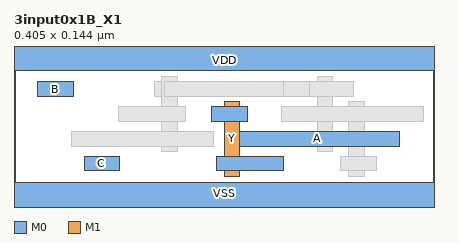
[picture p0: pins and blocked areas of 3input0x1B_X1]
MACRO 3input0x1B_X1
  CLASS CORE ;
  ORIGIN 0 0 ;
  FOREIGN 3input0x1B_X1 0 0 ;
  SIZE 0.4050 BY 0.1440 ;
  SYMMETRY X Y ;
  SITE coresite ;
  PIN A
    DIRECTION INPUT ;
    USE SIGNAL ;
    PORT
      LAYER M0 ;
        RECT 0.2130 0.0530 0.3720 0.0670 ;
    END
  END A
  PIN B
    DIRECTION INPUT ;
    USE SIGNAL ;
    PORT
      LAYER M0 ;
        RECT 0.0225 0.1010 0.0570 0.1150 ;
    END
  END B
  PIN C
    DIRECTION INPUT ;
    USE SIGNAL ;
    PORT
      LAYER M0 ;
        RECT 0.0675 0.0290 0.1020 0.0430 ;
    END
  END C
  PIN Y
    DIRECTION OUTPUT ;
    USE SIGNAL ;
    PORT
      LAYER M1 ;
        RECT 0.2025 0.0240 0.2175 0.0960 ;
      LAYER M0 ;
        RECT 0.1905 0.0770 0.2250 0.0910 ;
        RECT 0.1950 0.0290 0.2595 0.0430 ;
    END
  END Y
  PIN VDD
    DIRECTION INOUT ;
    USE POWER ;
    SHAPE ABUTMENT ;
    PORT
      LAYER M0 ;
        RECT 0.0000 0.1260 0.4050 0.1620 ;
    END
  END VDD
  PIN VSS
    DIRECTION INOUT ;
    USE GROUND ;
    SHAPE ABUTMENT ;
    PORT
      LAYER M0 ;
        RECT 0.0000 -0.0180 0.4050 0.0180 ;
    END
  END VSS
  OBS
    LAYER M2 ;
      RECT 0.1350 0.1010 0.3150 0.1150 ;
    LAYER V1 ;
      RECT 0.1430 0.1010 0.1570 0.1150 ;
      RECT 0.2930 0.1010 0.3070 0.1150 ;
    LAYER M1 ;
      RECT 0.3225 0.0240 0.3375 0.0960 ;
      RECT 0.1425 0.0480 0.1575 0.1200 ;
      RECT 0.2925 0.0480 0.3075 0.1200 ;
    LAYER V0 ;
      RECT 0.3230 0.0770 0.3370 0.0910 ;
      RECT 0.3230 0.0290 0.3370 0.0430 ;
      RECT 0.2030 0.0770 0.2170 0.0910 ;
      RECT 0.2030 0.0290 0.2170 0.0430 ;
      RECT 0.1430 0.0770 0.1570 0.0910 ;
      RECT 0.1430 0.0530 0.1570 0.0670 ;
      RECT 0.2930 0.1010 0.3070 0.1150 ;
    LAYER M0 ;
      RECT 0.3150 0.0290 0.3495 0.0430 ;
      RECT 0.0555 0.0530 0.1920 0.0670 ;
      RECT 0.1005 0.0770 0.1650 0.0910 ;
      RECT 0.2580 0.0770 0.3945 0.0910 ;
      RECT 0.1455 0.1010 0.2595 0.1150 ;
      RECT 0.2850 0.1010 0.3270 0.1150 ;
  END
END 3input0x1B_X1
